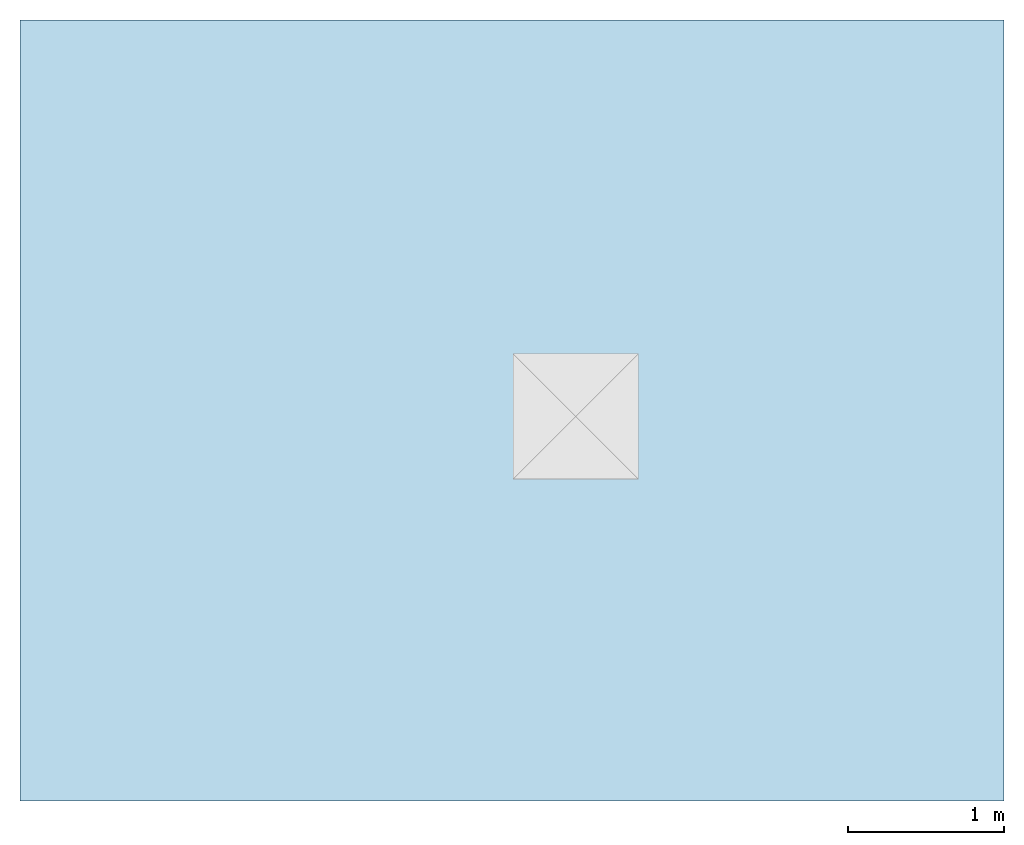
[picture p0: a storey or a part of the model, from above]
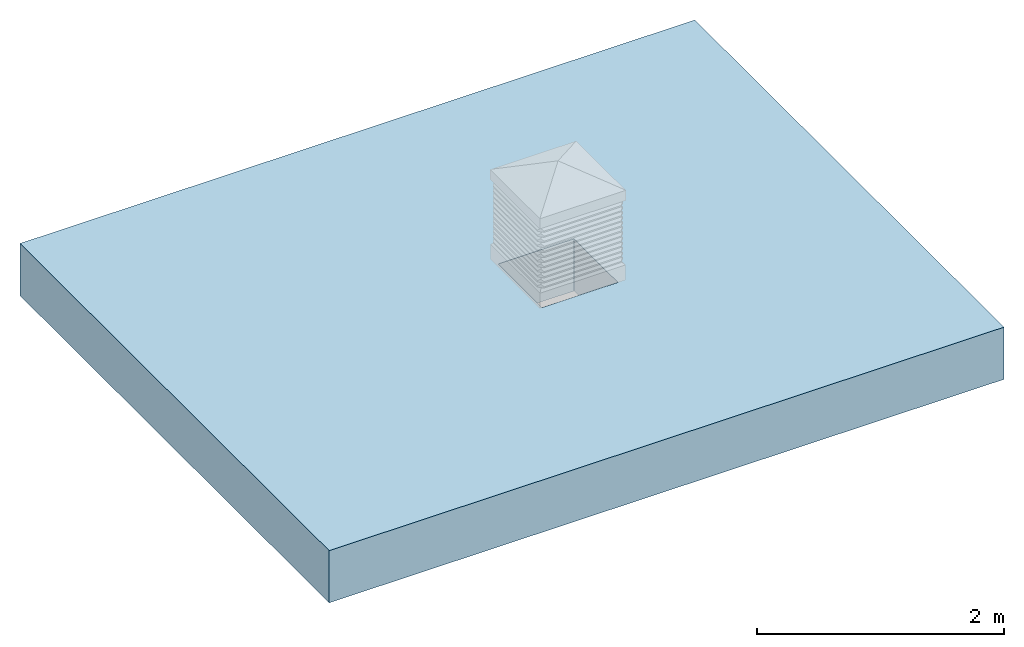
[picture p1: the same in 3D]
Properties of the parts of a building model (IFC2X3)

# File
Description: ViewDefinition [CoordinationView_V2.0], RevitIdentifiers [VersionGUID: b14b38f6-23d6-47e7-821c-de1b6eff49d6, NumberOfSaves: 0], CoordinateReference [CoordinateBase: Shared Coordinates, ProjectSite: Default Site]
File name: WBR_Passivent_NaturalVentilationSystems_AirstractRoofTerminal_800x800mm_June 2021.ifc
Time: 2025-06-25T10:59:30
Written by: ODA IFC SDK 22.8
Made in: 22.1.80.32 - IFC 22.7.0.0 - Default UI

# IfcProject, Project Number
LongName: Project Name; Phase: Project Status

# IfcSite, Default
RefLatitude: 51, 30, 23, 112487; RefLongitude: 0, -7, -37, -956022; RefElevation: 0 mm

# IfcBuilding
Pset_BuildingCommon - NumberOfStoreys: 1

# IfcBuildingStorey: Level:Circle Head - Project Datum (2)
Pset_AirSideSystemInformation - sets with these values: 2
Name | LongName = Name | Elevation (mm)
Level 0 | Level 0 | 0
Level 1 | Level 1 | 4000

# IfcFlowTerminal: WBR_Passivent_NaturalVentilationSystems_AirstractRoofTerminal_800x800mm_June 2021:AirstractRoofTerminal_800x800mm, WBR_Passivent_NaturalVentilationSystems_AirstractRoofTerminal_800x800mm_June 2021:AirstractRoofTerminal_800x800mm:313568
In: Level 0
Type - PredefinedType: GRILLE; Material: WBR_Passivent_Aluminum
Type - Pset_AirTerminalTypeCommon - Shape: RECTANGULAR
Type - Pset_ElementShading - Color: RAL 9016
Type - Pset_ManufacturerTypeInformation - ModelReference: Airstract Roof Terminal 800x800mm; Manufacturer: Passivent
Type - Pset_ProductRequirements - Name: NaturalVentilationSystems_AirstractRoofTerminal_Passivent
Pset_DistributionFlowElementCommon - Reference: AirstractRoofTerminal_800x800mm; sets with these values: 2
Pset_ManufacturerOccurrence - BarCode: n/a; SerialNumber: n/a

# IfcOpeningElement: Opening, Basic Roof:Roof_Pitched-50SS-220Ins-20MPan-225Purl:313548:1
In: Level 0
Pset_OpeningElementCommon - Reference: Roof_Pitched-50SS-220Ins-20MPan-225Purl; sets with these values: 2

# IfcRoof: Basic Roof:Roof_Pitched-50SS-220Ins-20MPan-225Purl, Basic Roof:Roof_Pitched-50SS-220Ins-20MPan-225Purl:313548
In: Level 0
Material: Roofing, Standing Seam 50 mm, Rigid insulation 220 mm, Metal Panel 20 mm, Steel Purlins 225 mm
Pset_QuantityTakeOff - Reference: Roof_Pitched-50SS-220Ins-20MPan-225Purl
Pset_RoofCommon - Reference: Roof_Pitched-50SS-220Ins-20MPan-225Purl; IsExternal: yes; ProjectedArea: 31.5 m2; TotalArea: 30.9973 m2

# IfcSlab: Basic Roof:Roof_Pitched-50SS-220Ins-20MPan-225Purl, Basic Roof:Roof_Pitched-50SS-220Ins-20MPan-225Purl:313548:1
In: Level 0
Type - PredefinedType: ROOF
Type - Pset_SlabCommon - IsExternal: yes; ThermalTransmittance: 0.158928 kg/K/s3
Pset_QuantityTakeOff - Reference: Roof_Pitched-50SS-220Ins-20MPan-225Purl; sets with these values: 2
Pset_SlabCommon - Reference: Roof_Pitched-50SS-220Ins-20MPan-225Purl; PitchAngle: 0 deg
